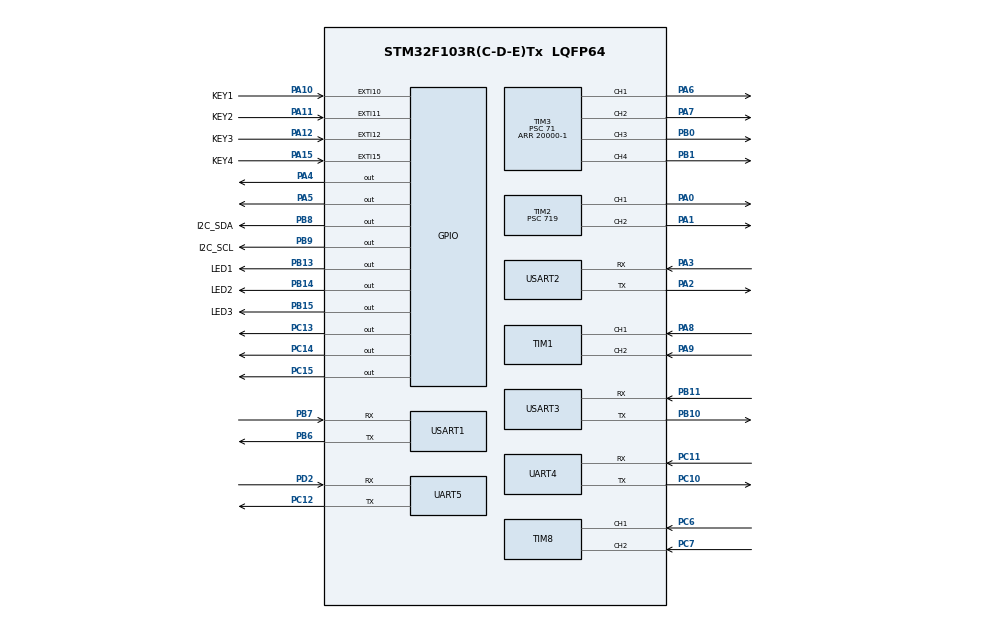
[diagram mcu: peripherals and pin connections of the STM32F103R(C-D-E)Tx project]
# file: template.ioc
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Mcu.Family=STM32F1
Mcu.Name=STM32F103R(C-D-E)Tx
Mcu.Package=LQFP64
NVIC.EXTI15_10_IRQn=true\:1\:0\:true\:false\:true\:true\:true\:true
NVIC.PriorityGroup=NVIC_PRIORITYGROUP_4
NVIC.TIM2_IRQn=true\:1\:0\:true\:false\:true\:true\:true\:true
NVIC.USART1_IRQn=true\:2\:0\:true\:false\:true\:true\:true\:true
NVIC.USART2_IRQn=true\:2\:0\:true\:false\:true\:true\:true\:true
NVIC.USART3_IRQn=true\:2\:0\:true\:false\:true\:true\:true\:true
PA0-WKUP.Signal=S_TIM2_CH1_ETR
PA1.Signal=S_TIM2_CH2
PA10.GPIO_Label=KEY1
PA10.Signal=GPXTI10
PA11.GPIO_Label=KEY2
PA11.Signal=GPXTI11
PA12.GPIO_Label=KEY3
PA12.Signal=GPXTI12
PA13.Mode=Serial_Wire
PA13.Signal=SYS_JTMS-SWDIO
PA14.Mode=Serial_Wire
PA14.Signal=SYS_JTCK-SWCLK
PA15.GPIO_Label=KEY4
PA15.Signal=GPXTI15
PA2.Mode=Asynchronous
PA2.Signal=USART2_TX
PA3.Mode=Asynchronous
PA3.Signal=USART2_RX
PA4.Signal=GPIO_Output
PA5.Signal=GPIO_Output
PA6.Signal=S_TIM3_CH1
PA7.Signal=S_TIM3_CH2
PA8.Signal=S_TIM1_CH1
PA9.Signal=S_TIM1_CH2
PB0.Signal=S_TIM3_CH3
PB1.Signal=S_TIM3_CH4
PB10.Mode=Asynchronous
PB10.Signal=USART3_TX
PB11.Mode=Asynchronous
PB11.Signal=USART3_RX
PB13.GPIO_Label=LED1
PB13.Signal=GPIO_Output
PB14.GPIO_Label=LED2
PB14.PinState=GPIO_PIN_SET
PB14.Signal=GPIO_Output
PB15.GPIO_Label=LED3
PB15.PinState=GPIO_PIN_SET
PB15.Signal=GPIO_Output
PB6.Mode=Asynchronous
PB6.Signal=USART1_TX
PB7.Mode=Asynchronous
PB7.Signal=USART1_RX
PB8.GPIO_Label=I2C_SDA
PB8.Signal=GPIO_Output
PB9.GPIO_Label=I2C_SCL
PB9.Signal=GPIO_Output
PC10.Mode=Asynchronous
PC10.Signal=UART4_TX
PC11.Mode=Asynchronous
PC11.Signal=UART4_RX
PC12.Mode=Asynchronous
PC12.Signal=UART5_TX
PC13-TAMPER-RTC.Signal=GPIO_Output
PC14-OSC32_IN.Signal=GPIO_Output
PC15-OSC32_OUT.Signal=GPIO_Output
PC6.Signal=S_TIM8_CH1
PC7.Signal=S_TIM8_CH2
PD0-OSC_IN.Mode=HSE-External-Oscillator
PD0-OSC_IN.Signal=RCC_OSC_IN
PD1-OSC_OUT.Mode=HSE-External-Oscillator
PD1-OSC_OUT.Signal=RCC_OSC_OUT
PD2.Mode=Asynchronous
PD2.Signal=UART5_RX
ProjectManager.HeapSize=0x200
ProjectManager.StackSize=0x400
ProjectManager.TargetToolchain=MDK-ARM V5.32
RCC.AHBFreq_Value=72000000
RCC.APB1CLKDivider=RCC_HCLK_DIV2
RCC.APB1Freq_Value=36000000
RCC.APB1TimFreq_Value=72000000
RCC.APB2Freq_Value=72000000
RCC.APB2TimFreq_Value=72000000
RCC.HCLKFreq_Value=72000000
RCC.PLLMUL=RCC_PLL_MUL9
RCC.PLLSourceVirtual=RCC_PLLSOURCE_HSE
RCC.SYSCLKFreq_VALUE=72000000
RCC.SYSCLKSource=RCC_SYSCLKSOURCE_PLLCLK
RCC.USBFreq_Value=72000000
SH.S_TIM1_CH1.0=TIM1_CH1,Encoder_Interface
SH.S_TIM1_CH2.0=TIM1_CH2,Encoder_Interface
SH.S_TIM2_CH1_ETR.0=TIM2_CH1,PWM Generation1 CH1
SH.S_TIM2_CH2.0=TIM2_CH2,PWM Generation2 CH2
SH.S_TIM3_CH1.0=TIM3_CH1,PWM Generation1 CH1
SH.S_TIM3_CH2.0=TIM3_CH2,PWM Generation2 CH2
SH.S_TIM3_CH3.0=TIM3_CH3,PWM Generation3 CH3
SH.S_TIM3_CH4.0=TIM3_CH4,PWM Generation4 CH4
SH.S_TIM8_CH1.0=TIM8_CH1,Encoder_Interface
SH.S_TIM8_CH2.0=TIM8_CH2,Encoder_Interface
TIM2.AutoReloadPreload=TIM_AUTORELOAD_PRELOAD_ENABLE
TIM2.Channel-PWM\ Generation1\ CH1=TIM_CHANNEL_1
TIM2.Channel-PWM\ Generation2\ CH2=TIM_CHANNEL_2
TIM2.Period=99
TIM2.Prescaler=719
TIM3.Channel-PWM\ Generation1\ CH1=TIM_CHANNEL_1
TIM3.Channel-PWM\ Generation2\ CH2=TIM_CHANNEL_2
TIM3.Channel-PWM\ Generation3\ CH3=TIM_CHANNEL_3
TIM3.Channel-PWM\ Generation4\ CH4=TIM_CHANNEL_4
TIM3.Period=20000-1
TIM3.Prescaler=71
UART4.VirtualMode=Asynchronous
UART5.VirtualMode=Asynchronous
USART1.VirtualMode=VM_ASYNC
USART2.VirtualMode=VM_ASYNC
USART3.VirtualMode=VM_ASYNC
VP_TIM2_VS_ClockSourceINT.Mode=Internal
board=custom

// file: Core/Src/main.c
/* USER CODE BEGIN Header */
/**
  ******************************************************************************
  * @file           : main.c
  * @brief          : Main program body
  ******************************************************************************
  * @attention
  *
  * Copyright (c) 2024 STMicroelectronics.
  * All rights reserved.
  *
  * This software is licensed under terms that can be found in the LICENSE file
  * in the root directory of this software component.
  * If no LICENSE file comes with this software, it is provided AS-IS.
  *
  ******************************************************************************
  */
/* USER CODE END Header */
#include "main.h"
#include "tim.h"
#include "usart.h"
#include "gpio.h"

/* USER CODE BEGIN Includes */
#include "app.h"
/* USER CODE END Includes */

void SystemClock_Config(void);

int main(void)
{

  /* MCU Configuration--------------------------------------------------------*/

  /* Reset of all peripherals, Initializes the Flash interface and the Systick. */
  HAL_Init();

  /* Configure the system clock */
  SystemClock_Config();

  /* Initialize all configured peripherals */
  MX_GPIO_Init();
  MX_UART4_Init();
  MX_USART1_UART_Init();
  MX_TIM1_Init();
  MX_TIM2_Init();
  MX_TIM3_Init();
  MX_TIM8_Init();
  MX_UART5_Init();
  MX_USART2_UART_Init();
  MX_USART3_UART_Init();
  /* USER CODE BEGIN 2 */
	App_Init();
  /* USER CODE END 2 */

  /* Infinite loop */
  while (1)
  {

    /* USER CODE BEGIN 3 */
		App_Task();
  }
  /* USER CODE END 3 */
}

void SystemClock_Config(void)
{
  RCC_OscInitTypeDef RCC_OscInitStruct = {0};
  RCC_ClkInitTypeDef RCC_ClkInitStruct = {0};

  /** Initializes the RCC Oscillators according to the specified parameters
  * in the RCC_OscInitTypeDef structure.
  */
	  // 先将时钟源选择为内部时钟
  RCC_ClkInitStruct.ClockType = RCC_CLOCKTYPE_SYSCLK;
  RCC_ClkInitStruct.SYSCLKSource = RCC_SYSCLKSOURCE_HSI;
//  if (HAL_RCC_ClockConfig(&RCC_ClkInitStruct, FLASH_LATENCY_5) != HAL_OK)
//  {
//    Error_Handler();
//  }

  RCC_OscInitStruct.OscillatorType = RCC_OSCILLATORTYPE_HSE;
  RCC_OscInitStruct.HSEState = RCC_HSE_ON;
  RCC_OscInitStruct.HSEPredivValue = RCC_HSE_PREDIV_DIV1;
  RCC_OscInitStruct.HSIState = RCC_HSI_ON;
  RCC_OscInitStruct.PLL.PLLState = RCC_PLL_ON;
  RCC_OscInitStruct.PLL.PLLSource = RCC_PLLSOURCE_HSE;
  RCC_OscInitStruct.PLL.PLLMUL = RCC_PLL_MUL9;
  if (HAL_RCC_OscConfig(&RCC_OscInitStruct) != HAL_OK)
  {
    Error_Handler();
  }

  /** Initializes the CPU, AHB and APB buses clocks
  */
  RCC_ClkInitStruct.ClockType = RCC_CLOCKTYPE_HCLK|RCC_CLOCKTYPE_SYSCLK
                              |RCC_CLOCKTYPE_PCLK1|RCC_CLOCKTYPE_PCLK2;
  RCC_ClkInitStruct.SYSCLKSource = RCC_SYSCLKSOURCE_PLLCLK;
  RCC_ClkInitStruct.AHBCLKDivider = RCC_SYSCLK_DIV1;
  RCC_ClkInitStruct.APB1CLKDivider = RCC_HCLK_DIV2;
  RCC_ClkInitStruct.APB2CLKDivider = RCC_HCLK_DIV1;

  if (HAL_RCC_ClockConfig(&RCC_ClkInitStruct, FLASH_LATENCY_2) != HAL_OK)
  {
    Error_Handler();
  }
}

void Error_Handler(void)
{
  __disable_irq();
  while (1)
  {
  }
}
